VERSION 5.8 ;
BUSBITCHARS "[]" ;
DIVIDERCHAR "/" ;
UNITS
    DATABASE MICRONS 1000 ;
END UNITS

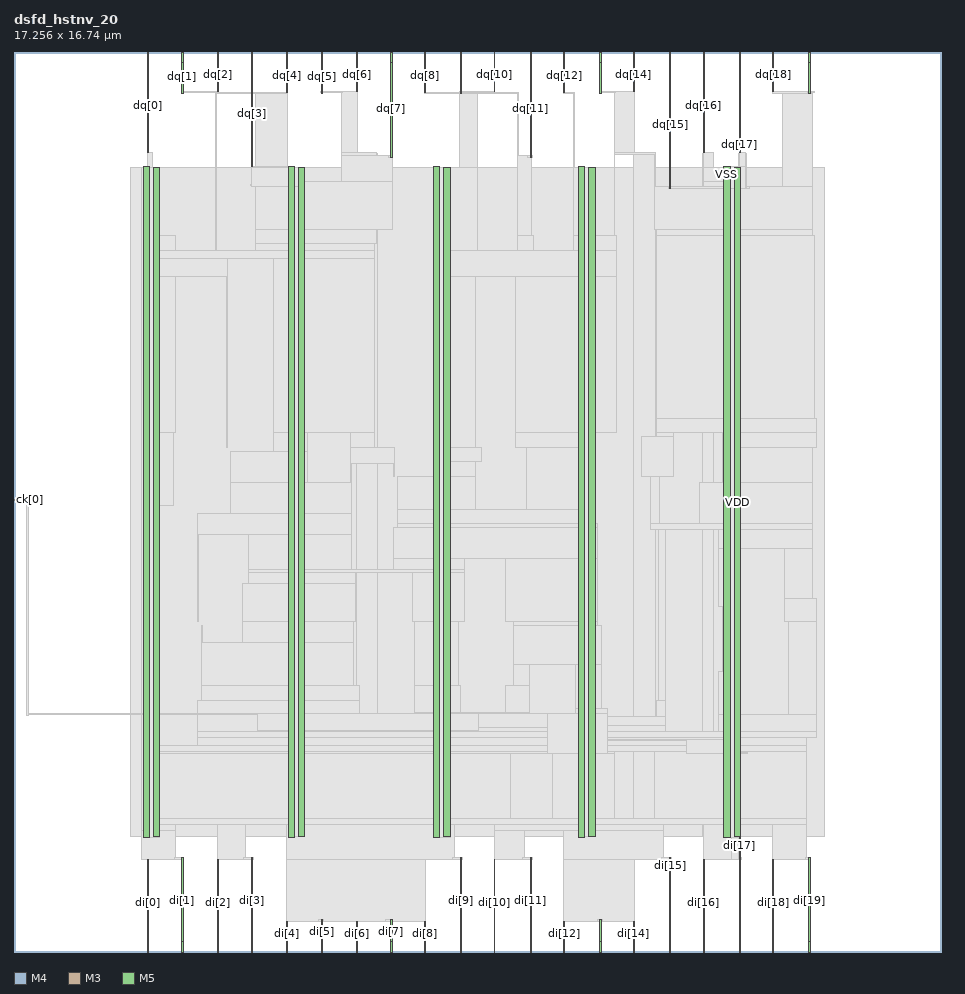
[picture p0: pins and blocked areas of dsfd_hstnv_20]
MACRO dsfd_hstnv_20
  FOREIGN dsfd_hstnv_20 0 0 ;
  CLASS BLOCK ;
  SIZE 17.256 BY 16.74 ;
  PIN ck[0]
    DIRECTION INPUT ;
    USE SIGNAL ;
    PORT
      LAYER M4 ;
        RECT  0 8.4 0.192 8.424 ;
    END
    PORT
      LAYER M4 ;
        RECT  0.156 8.4 0.275 8.424 ;
    END
  END ck[0]
  PIN di[0]
    DIRECTION INPUT ;
    USE SIGNAL ;
    PORT
      LAYER M3 ;
        RECT  2.484 0 2.502 0.144 ;
    END
    PORT
      LAYER M3 ;
        RECT  2.484 0.108 2.502 1.723 ;
    END
  END di[0]
  PIN di[10]
    DIRECTION INPUT ;
    USE SIGNAL ;
    PORT
      LAYER M3 ;
        RECT  8.928 0 8.946 0.144 ;
    END
    PORT
      LAYER M3 ;
        RECT  8.928 0.108 8.946 1.723 ;
    END
  END di[10]
  PIN di[11]
    DIRECTION INPUT ;
    USE SIGNAL ;
    PORT
      LAYER M5 ;
        RECT  9.6 0 9.624 0.192 ;
    END
    PORT
      LAYER M5 ;
        RECT  9.6 0.144 9.624 1.763 ;
    END
  END di[11]
  PIN di[12]
    DIRECTION INPUT ;
    USE SIGNAL ;
    PORT
      LAYER M3 ;
        RECT  10.224 0 10.242 0.144 ;
    END
    PORT
      LAYER M3 ;
        RECT  10.224 0.108 10.242 0.571 ;
    END
  END di[12]
  PIN di[13]
    DIRECTION INPUT ;
    USE SIGNAL ;
    PORT
      LAYER M5 ;
        RECT  10.896 0 10.92 0.192 ;
    END
    PORT
      LAYER M5 ;
        RECT  10.896 0.144 10.92 0.611 ;
    END
  END di[13]
  PIN di[14]
    DIRECTION INPUT ;
    USE SIGNAL ;
    PORT
      LAYER M3 ;
        RECT  11.52 0 11.538 0.144 ;
    END
    PORT
      LAYER M3 ;
        RECT  11.52 0.108 11.538 0.571 ;
    END
  END di[14]
  PIN di[15]
    DIRECTION INPUT ;
    USE SIGNAL ;
    PORT
      LAYER M5 ;
        RECT  12.192 0 12.216 0.192 ;
    END
    PORT
      LAYER M5 ;
        RECT  12.192 0.144 12.216 1.763 ;
    END
  END di[15]
  PIN di[16]
    DIRECTION INPUT ;
    USE SIGNAL ;
    PORT
      LAYER M3 ;
        RECT  12.816 0 12.834 0.144 ;
    END
    PORT
      LAYER M3 ;
        RECT  12.816 0.108 12.834 1.723 ;
    END
  END di[16]
  PIN di[17]
    DIRECTION INPUT ;
    USE SIGNAL ;
    PORT
      LAYER M5 ;
        RECT  13.488 0 13.512 0.192 ;
    END
    PORT
      LAYER M5 ;
        RECT  13.488 0.144 13.512 2.137 ;
    END
  END di[17]
  PIN di[18]
    DIRECTION INPUT ;
    USE SIGNAL ;
    PORT
      LAYER M3 ;
        RECT  14.112 0 14.13 0.144 ;
    END
    PORT
      LAYER M3 ;
        RECT  14.112 0.108 14.13 1.723 ;
    END
  END di[18]
  PIN di[19]
    DIRECTION INPUT ;
    USE SIGNAL ;
    PORT
      LAYER M5 ;
        RECT  14.784 0 14.808 0.192 ;
    END
    PORT
      LAYER M5 ;
        RECT  14.784 0.144 14.808 1.763 ;
    END
  END di[19]
  PIN di[1]
    DIRECTION INPUT ;
    USE SIGNAL ;
    PORT
      LAYER M5 ;
        RECT  3.12 0 3.144 0.192 ;
    END
    PORT
      LAYER M5 ;
        RECT  3.12 0.144 3.144 1.763 ;
    END
  END di[1]
  PIN di[2]
    DIRECTION INPUT ;
    USE SIGNAL ;
    PORT
      LAYER M3 ;
        RECT  3.78 0 3.798 0.144 ;
    END
    PORT
      LAYER M3 ;
        RECT  3.78 0.108 3.798 1.723 ;
    END
  END di[2]
  PIN di[3]
    DIRECTION INPUT ;
    USE SIGNAL ;
    PORT
      LAYER M5 ;
        RECT  4.416 0 4.44 0.192 ;
    END
    PORT
      LAYER M5 ;
        RECT  4.416 0.144 4.44 1.763 ;
    END
  END di[3]
  PIN di[4]
    DIRECTION INPUT ;
    USE SIGNAL ;
    PORT
      LAYER M3 ;
        RECT  5.076 0 5.094 0.144 ;
    END
    PORT
      LAYER M3 ;
        RECT  5.076 0.108 5.094 0.571 ;
    END
  END di[4]
  PIN di[5]
    DIRECTION INPUT ;
    USE SIGNAL ;
    PORT
      LAYER M5 ;
        RECT  5.712 0 5.736 0.192 ;
    END
    PORT
      LAYER M5 ;
        RECT  5.712 0.144 5.736 0.611 ;
    END
  END di[5]
  PIN di[6]
    DIRECTION INPUT ;
    USE SIGNAL ;
    PORT
      LAYER M3 ;
        RECT  6.372 0 6.39 0.144 ;
    END
    PORT
      LAYER M3 ;
        RECT  6.372 0.108 6.39 0.571 ;
    END
  END di[6]
  PIN di[7]
    DIRECTION INPUT ;
    USE SIGNAL ;
    PORT
      LAYER M5 ;
        RECT  7.008 0 7.032 0.192 ;
    END
    PORT
      LAYER M5 ;
        RECT  7.008 0.144 7.032 0.611 ;
    END
  END di[7]
  PIN di[8]
    DIRECTION INPUT ;
    USE SIGNAL ;
    PORT
      LAYER M3 ;
        RECT  7.632 0 7.65 0.144 ;
    END
    PORT
      LAYER M3 ;
        RECT  7.632 0.108 7.65 0.571 ;
    END
  END di[8]
  PIN di[9]
    DIRECTION INPUT ;
    USE SIGNAL ;
    PORT
      LAYER M5 ;
        RECT  8.304 0 8.328 0.192 ;
    END
    PORT
      LAYER M5 ;
        RECT  8.304 0.144 8.328 1.763 ;
    END
  END di[9]
  PIN dq[0]
    DIRECTION OUTPUT ;
    USE SIGNAL ;
    PORT
      LAYER M3 ;
        RECT  2.484 16.596 2.502 16.74 ;
    END
    PORT
      LAYER M3 ;
        RECT  2.484 14.864 2.502 16.62 ;
    END
  END dq[0]
  PIN dq[10]
    DIRECTION OUTPUT ;
    USE SIGNAL ;
    PORT
      LAYER M3 ;
        RECT  8.928 16.596 8.946 16.74 ;
    END
    PORT
      LAYER M3 ;
        RECT  8.928 16.013 8.946 16.62 ;
    END
  END dq[10]
  PIN dq[11]
    DIRECTION OUTPUT ;
    USE SIGNAL ;
    PORT
      LAYER M5 ;
        RECT  9.6 16.548 9.624 16.74 ;
    END
    PORT
      LAYER M5 ;
        RECT  9.6 14.773 9.624 16.592 ;
    END
  END dq[11]
  PIN dq[12]
    DIRECTION OUTPUT ;
    USE SIGNAL ;
    PORT
      LAYER M3 ;
        RECT  10.224 16.596 10.242 16.74 ;
    END
    PORT
      LAYER M3 ;
        RECT  10.224 15.989 10.242 16.62 ;
    END
  END dq[12]
  PIN dq[13]
    DIRECTION OUTPUT ;
    USE SIGNAL ;
    PORT
      LAYER M5 ;
        RECT  10.896 16.548 10.92 16.74 ;
    END
    PORT
      LAYER M5 ;
        RECT  10.896 15.973 10.92 16.592 ;
    END
  END dq[13]
  PIN dq[14]
    DIRECTION OUTPUT ;
    USE SIGNAL ;
    PORT
      LAYER M3 ;
        RECT  11.52 16.596 11.538 16.74 ;
    END
    PORT
      LAYER M3 ;
        RECT  11.52 16.013 11.538 16.62 ;
    END
  END dq[14]
  PIN dq[15]
    DIRECTION OUTPUT ;
    USE SIGNAL ;
    PORT
      LAYER M5 ;
        RECT  12.192 16.548 12.216 16.74 ;
    END
    PORT
      LAYER M5 ;
        RECT  12.192 14.197 12.216 16.592 ;
    END
  END dq[15]
  PIN dq[16]
    DIRECTION OUTPUT ;
    USE SIGNAL ;
    PORT
      LAYER M3 ;
        RECT  12.816 16.596 12.834 16.74 ;
    END
    PORT
      LAYER M3 ;
        RECT  12.816 14.864 12.834 16.62 ;
    END
  END dq[16]
  PIN dq[17]
    DIRECTION OUTPUT ;
    USE SIGNAL ;
    PORT
      LAYER M5 ;
        RECT  13.488 16.548 13.512 16.74 ;
    END
    PORT
      LAYER M5 ;
        RECT  13.488 14.867 13.512 16.592 ;
    END
  END dq[17]
  PIN dq[18]
    DIRECTION OUTPUT ;
    USE SIGNAL ;
    PORT
      LAYER M3 ;
        RECT  14.112 16.596 14.13 16.74 ;
    END
    PORT
      LAYER M3 ;
        RECT  14.112 16.013 14.13 16.62 ;
    END
  END dq[18]
  PIN dq[19]
    DIRECTION OUTPUT ;
    USE SIGNAL ;
    PORT
      LAYER M5 ;
        RECT  14.784 16.548 14.808 16.74 ;
    END
    PORT
      LAYER M5 ;
        RECT  14.784 15.973 14.808 16.592 ;
    END
  END dq[19]
  PIN dq[1]
    DIRECTION OUTPUT ;
    USE SIGNAL ;
    PORT
      LAYER M5 ;
        RECT  3.12 16.548 3.144 16.74 ;
    END
    PORT
      LAYER M5 ;
        RECT  3.12 15.973 3.144 16.592 ;
    END
  END dq[1]
  PIN dq[2]
    DIRECTION OUTPUT ;
    USE SIGNAL ;
    PORT
      LAYER M3 ;
        RECT  3.78 16.596 3.798 16.74 ;
    END
    PORT
      LAYER M3 ;
        RECT  3.78 16.013 3.798 16.62 ;
    END
  END dq[2]
  PIN dq[3]
    DIRECTION OUTPUT ;
    USE SIGNAL ;
    PORT
      LAYER M5 ;
        RECT  4.416 16.548 4.44 16.74 ;
    END
    PORT
      LAYER M5 ;
        RECT  4.416 14.603 4.44 16.592 ;
    END
  END dq[3]
  PIN dq[4]
    DIRECTION OUTPUT ;
    USE SIGNAL ;
    PORT
      LAYER M3 ;
        RECT  5.076 16.596 5.094 16.74 ;
    END
    PORT
      LAYER M3 ;
        RECT  5.076 15.989 5.094 16.62 ;
    END
  END dq[4]
  PIN dq[5]
    DIRECTION OUTPUT ;
    USE SIGNAL ;
    PORT
      LAYER M5 ;
        RECT  5.712 16.548 5.736 16.74 ;
    END
    PORT
      LAYER M5 ;
        RECT  5.712 15.973 5.736 16.592 ;
    END
  END dq[5]
  PIN dq[6]
    DIRECTION OUTPUT ;
    USE SIGNAL ;
    PORT
      LAYER M3 ;
        RECT  6.372 16.596 6.39 16.74 ;
    END
    PORT
      LAYER M3 ;
        RECT  6.372 16.013 6.39 16.62 ;
    END
  END dq[6]
  PIN dq[7]
    DIRECTION OUTPUT ;
    USE SIGNAL ;
    PORT
      LAYER M5 ;
        RECT  7.008 16.548 7.032 16.74 ;
    END
    PORT
      LAYER M5 ;
        RECT  7.008 14.773 7.032 16.592 ;
    END
  END dq[7]
  PIN dq[8]
    DIRECTION OUTPUT ;
    USE SIGNAL ;
    PORT
      LAYER M3 ;
        RECT  7.632 16.596 7.65 16.74 ;
    END
    PORT
      LAYER M3 ;
        RECT  7.632 15.989 7.65 16.62 ;
    END
  END dq[8]
  PIN dq[9]
    DIRECTION OUTPUT ;
    USE SIGNAL ;
    PORT
      LAYER M5 ;
        RECT  8.304 16.548 8.328 16.74 ;
    END
    PORT
      LAYER M5 ;
        RECT  8.304 15.973 8.328 16.592 ;
    END
  END dq[9]
  PIN VDD
    DIRECTION INOUT ;
    USE POWER ;
    PORT
      LAYER M5 ;
        RECT  13.392 2.151 13.512 14.589 ;
        RECT  10.692 2.151 10.812 14.589 ;
        RECT  7.992 2.151 8.112 14.589 ;
        RECT  5.292 2.151 5.412 14.589 ;
        RECT  2.592 2.151 2.712 14.589 ;
    END
  END VDD
  PIN VSS
    DIRECTION INOUT ;
    USE GROUND ;
    PORT
      LAYER M5 ;
        RECT  13.2 2.137 13.32 14.603 ;
        RECT  10.5 2.137 10.62 14.603 ;
        RECT  7.8 2.137 7.92 14.603 ;
        RECT  5.1 2.137 5.22 14.603 ;
        RECT  2.4 2.137 2.52 14.603 ;
    END
  END VSS
  # OT_OBS_CLOSED layer=M5 d_um=1.536 added=0
  OBS
    LAYER RVTN ;
     RECT  2.16 2.16 15.066 2.295 ;
     RECT  2.16 2.565 15.066 2.835 ;
     RECT  2.16 3.105 15.066 3.375 ;
     RECT  2.16 3.645 15.066 3.915 ;
     RECT  2.16 4.185 15.066 4.455 ;
     RECT  2.16 4.725 15.066 4.995 ;
     RECT  2.16 5.265 15.066 5.535 ;
     RECT  2.16 5.805 15.066 6.075 ;
     RECT  2.16 6.345 15.066 6.615 ;
     RECT  2.16 6.885 15.066 7.155 ;
     RECT  2.16 7.425 15.066 7.695 ;
     RECT  2.16 7.965 15.066 8.235 ;
     RECT  2.16 8.505 15.066 8.775 ;
     RECT  2.16 9.045 15.066 9.315 ;
     RECT  2.16 9.585 15.066 9.855 ;
     RECT  2.16 10.125 15.066 10.395 ;
     RECT  2.16 10.665 15.066 10.935 ;
     RECT  2.16 11.205 15.066 11.475 ;
     RECT  2.16 11.745 15.066 12.015 ;
     RECT  2.16 12.285 15.066 12.555 ;
     RECT  2.16 12.825 15.066 13.095 ;
     RECT  2.16 13.365 15.066 13.635 ;
     RECT  2.16 13.905 15.066 14.175 ;
     RECT  2.16 14.445 15.066 14.58 ;
    LAYER RVTP ;
     RECT  2.16 2.295 15.066 2.565 ;
     RECT  2.16 2.835 15.066 3.105 ;
     RECT  2.16 3.375 15.066 3.645 ;
     RECT  2.16 3.915 15.066 4.185 ;
     RECT  2.16 4.455 15.066 4.725 ;
     RECT  2.16 4.995 15.066 5.265 ;
     RECT  2.16 5.535 15.066 5.805 ;
     RECT  2.16 6.075 15.066 6.345 ;
     RECT  2.16 6.615 15.066 6.885 ;
     RECT  2.16 7.155 15.066 7.425 ;
     RECT  2.16 7.695 15.066 7.965 ;
     RECT  2.16 8.235 15.066 8.505 ;
     RECT  2.16 8.775 15.066 9.045 ;
     RECT  2.16 9.315 15.066 9.585 ;
     RECT  2.16 9.855 15.066 10.125 ;
     RECT  2.16 10.395 15.066 10.665 ;
     RECT  2.16 10.935 15.066 11.205 ;
     RECT  2.16 11.475 15.066 11.745 ;
     RECT  2.16 12.015 15.066 12.285 ;
     RECT  2.16 12.555 15.066 12.825 ;
     RECT  2.16 13.095 15.066 13.365 ;
     RECT  2.16 13.635 15.066 13.905 ;
     RECT  2.16 14.175 15.066 14.445 ;
    LAYER M1 ;
     RECT  2.16 2.151 15.066 14.589 ;
    LAYER M2 ;
     RECT  2.16 2.151 2.371 14.589 ;
     RECT  2.371 1.728 2.479 14.589 ;
     RECT  2.479 1.728 2.507 14.859 ;
     RECT  2.507 2.151 2.579 14.859 ;
     RECT  3.775 15.966 4.523 15.984 ;
     RECT  2.579 2.151 6.367 14.589 ;
     RECT  6.367 2.151 6.755 14.859 ;
     RECT  7.627 15.966 9.383 15.984 ;
     RECT  10.219 15.966 10.427 15.984 ;
     RECT  6.755 2.151 11.515 14.589 ;
     RECT  11.515 2.151 11.939 14.859 ;
     RECT  11.939 2.151 12.811 14.589 ;
     RECT  12.811 2.151 13.019 14.859 ;
     RECT  14.107 15.966 14.315 15.984 ;
     RECT  13.019 2.151 15.066 14.589 ;
    LAYER M3 ;
     RECT  5.076 0.571 7.65 1.723 ;
     RECT  10.224 0.571 11.538 1.723 ;
     RECT  2.376 1.723 3.006 2.255 ;
     RECT  8.928 1.723 9.486 2.263 ;
     RECT  10.224 1.723 12.078 2.263 ;
     RECT  2.415 2.255 3.006 2.371 ;
     RECT  3.78 1.723 4.302 2.371 ;
     RECT  5.076 1.723 8.19 2.371 ;
     RECT  8.928 2.263 12.078 2.371 ;
     RECT  12.816 1.723 13.374 2.371 ;
     RECT  14.112 1.723 14.742 2.371 ;
     RECT  2.415 2.371 14.742 2.489 ;
     RECT  2.415 2.489 9.234 3.691 ;
     RECT  10.008 2.489 11.178 3.691 ;
     RECT  2.415 3.691 11.178 3.721 ;
     RECT  11.916 2.489 14.742 3.721 ;
     RECT  2.415 3.721 14.742 3.839 ;
     RECT  3.42 3.839 14.742 3.991 ;
     RECT  3.42 3.991 14.922 4.109 ;
     RECT  7.452 4.109 12.114 4.205 ;
     RECT  10.44 4.205 12.114 4.379 ;
     RECT  13.104 4.109 14.922 4.415 ;
     RECT  7.452 4.205 9.594 4.451 ;
     RECT  10.44 4.379 11.034 4.523 ;
     RECT  3.42 4.109 6.426 4.685 ;
     RECT  11.952 4.379 12.114 4.685 ;
     RECT  3.492 4.685 6.426 4.955 ;
     RECT  7.452 4.451 8.298 4.955 ;
     RECT  9.144 4.451 9.594 4.955 ;
     RECT  13.104 4.415 13.497 5.225 ;
     RECT  9.288 4.955 9.594 5.341 ;
     RECT  10.44 4.523 10.926 5.341 ;
     RECT  3.492 4.955 6.318 5.765 ;
     RECT  3.492 5.765 3.51 6.071 ;
     RECT  9.288 5.341 10.926 6.071 ;
     RECT  4.248 5.765 6.318 6.151 ;
     RECT  7.452 4.955 8.262 6.151 ;
     RECT  9.288 6.071 10.854 6.151 ;
     RECT  14.4 4.415 14.922 6.151 ;
     RECT  13.176 5.225 13.497 6.421 ;
     RECT  14.328 6.151 14.922 6.575 ;
     RECT  4.248 6.151 6.354 6.845 ;
     RECT  4.356 6.845 6.354 7.051 ;
     RECT  7.416 6.151 8.37 7.051 ;
     RECT  4.356 7.051 8.37 7.115 ;
     RECT  7.056 7.115 8.37 7.321 ;
     RECT  9.144 6.151 10.854 7.321 ;
     RECT  13.104 6.421 13.497 7.501 ;
     RECT  14.328 6.575 14.85 7.501 ;
     RECT  3.42 6.151 3.438 7.771 ;
     RECT  4.356 7.115 6.282 7.771 ;
     RECT  11.988 4.685 12.114 7.861 ;
     RECT  13.104 7.501 14.85 7.861 ;
     RECT  7.056 7.321 10.854 7.889 ;
     RECT  7.128 7.889 10.854 7.961 ;
     RECT  11.844 7.861 14.85 7.961 ;
     RECT  3.42 7.771 6.282 8.159 ;
     RECT  7.128 7.961 10.797 8.231 ;
     RECT  2.415 3.839 2.697 8.311 ;
     RECT  4.032 8.159 6.282 8.735 ;
     RECT  12.744 7.961 14.85 8.735 ;
     RECT  7.128 8.231 8.586 8.843 ;
     RECT  11.844 7.961 12.006 8.851 ;
     RECT  6.264 8.735 6.282 9.085 ;
     RECT  7.056 8.851 7.074 9.085 ;
     RECT  7.815 8.843 8.586 9.121 ;
     RECT  4.032 8.735 5.454 9.311 ;
     RECT  6.264 9.085 7.074 9.383 ;
     RECT  7.815 9.121 8.694 9.383 ;
     RECT  9.54 8.231 10.797 9.391 ;
     RECT  13.176 8.735 14.85 9.391 ;
     RECT  11.664 8.851 12.258 9.581 ;
     RECT  2.415 8.311 2.97 9.661 ;
     RECT  4.824 9.311 5.454 9.661 ;
     RECT  6.264 9.383 6.714 9.661 ;
     RECT  9.324 9.391 10.797 9.661 ;
     RECT  11.952 9.581 12.258 9.661 ;
     RECT  13.176 9.391 14.922 9.661 ;
     RECT  11.952 9.661 14.922 9.923 ;
     RECT  2.415 9.661 3.006 12.559 ;
     RECT  3.96 9.391 3.978 12.559 ;
     RECT  7.815 9.383 8.586 12.559 ;
     RECT  9.324 9.661 11.214 12.559 ;
     RECT  2.415 12.559 3.978 12.901 ;
     RECT  4.824 9.661 6.714 12.901 ;
     RECT  2.415 12.901 6.714 13.055 ;
     RECT  7.815 12.559 11.214 13.055 ;
     RECT  4.5 13.055 6.714 13.171 ;
     RECT  2.415 13.055 3.006 13.325 ;
     RECT  9.36 13.055 9.666 13.325 ;
     RECT  10.404 13.055 11.214 13.325 ;
     RECT  11.952 9.923 14.886 13.325 ;
     RECT  4.5 13.171 6.75 13.441 ;
     RECT  11.952 13.325 14.85 13.441 ;
     RECT  11.916 13.441 14.85 14.237 ;
     RECT  2.415 13.325 2.697 14.327 ;
     RECT  4.5 13.441 7.038 14.327 ;
     RECT  12.816 14.237 13.497 14.327 ;
     RECT  2.415 14.327 2.574 14.597 ;
     RECT  4.5 14.327 5.205 14.597 ;
     RECT  7.815 13.055 8.622 14.597 ;
     RECT  10.404 13.325 11.178 14.597 ;
     RECT  12.816 14.327 13.305 14.597 ;
     RECT  6.084 14.327 7.038 14.813 ;
     RECT  9.36 13.325 9.63 14.813 ;
     RECT  11.16 14.597 11.178 14.836 ;
     RECT  11.916 14.237 11.934 14.836 ;
     RECT  2.484 14.597 2.574 14.864 ;
     RECT  6.084 14.813 6.75 14.864 ;
     RECT  11.16 14.836 11.934 14.864 ;
     RECT  12.816 14.597 13.014 14.864 ;
     RECT  3.744 13.055 3.762 15.961 ;
     RECT  4.5 14.597 5.094 15.961 ;
     RECT  8.28 14.597 8.622 15.961 ;
     RECT  9.36 14.813 9.378 15.961 ;
     RECT  10.404 14.597 10.422 15.961 ;
     RECT  14.292 14.237 14.85 15.961 ;
     RECT  3.744 15.961 5.094 15.989 ;
     RECT  7.632 15.961 9.378 15.989 ;
     RECT  10.224 15.961 10.422 15.989 ;
     RECT  3.744 15.989 3.798 16.013 ;
     RECT  6.084 14.864 6.39 16.013 ;
     RECT  8.604 15.989 8.946 16.013 ;
     RECT  11.16 14.864 11.538 16.013 ;
     RECT  14.112 15.961 14.85 16.013 ;
    LAYER M4 ;
     RECT  0.229 4.416 2.408 4.44 ;
     RECT  2.408 2.148 2.512 14.592 ;
     RECT  2.512 2.148 2.704 14.322 ;
     RECT  2.977 1.728 3.155 1.752 ;
     RECT  3.109 15.984 3.773 16.008 ;
     RECT  4.273 1.728 4.451 1.752 ;
     RECT  2.704 4.416 4.525 4.44 ;
     RECT  4.525 4.128 5.108 4.44 ;
     RECT  4.405 14.256 5.108 14.28 ;
     RECT  5.108 2.148 5.212 14.592 ;
     RECT  5.212 2.418 5.404 14.322 ;
     RECT  5.669 0.576 5.753 0.6 ;
     RECT  5.701 15.984 6.113 16.008 ;
     RECT  6.901 0.576 7.043 0.6 ;
     RECT  6.965 14.784 7.049 14.808 ;
     RECT  5.404 4.128 7.808 4.44 ;
     RECT  7.808 2.148 7.912 14.592 ;
     RECT  7.912 2.148 8.104 14.322 ;
     RECT  8.161 1.728 8.339 1.752 ;
     RECT  8.104 4.128 8.633 4.44 ;
     RECT  8.293 15.984 8.633 16.008 ;
     RECT  9.457 1.728 9.635 1.752 ;
     RECT  9.557 14.784 9.641 14.808 ;
     RECT  8.633 4.176 9.925 4.44 ;
     RECT  9.925 3.696 10.508 4.44 ;
     RECT  10.508 2.148 10.612 14.592 ;
     RECT  10.612 2.418 10.804 14.322 ;
     RECT  10.861 0.576 10.945 0.6 ;
     RECT  10.804 3.696 11.045 4.44 ;
     RECT  10.885 15.984 11.189 16.008 ;
     RECT  12.049 1.728 12.227 1.752 ;
     RECT  11.045 3.936 12.517 3.96 ;
     RECT  12.517 3.696 13.208 3.96 ;
     RECT  12.181 14.208 13.208 14.232 ;
     RECT  13.208 2.148 13.345 14.592 ;
     RECT  13.345 1.728 13.477 14.592 ;
     RECT  13.477 1.728 13.504 14.856 ;
     RECT  13.504 1.728 13.523 1.752 ;
     RECT  13.504 14.208 13.619 14.856 ;
     RECT  13.504 3.696 13.637 3.72 ;
     RECT  13.619 14.208 13.673 14.232 ;
     RECT  14.713 1.728 14.819 1.752 ;
     RECT  14.757 15.984 14.88 16.008 ;
    LAYER M5 ;
     RECT  5.1 2.137 5.22 2.151 ;
     RECT  10.5 2.137 10.62 2.151 ;
     RECT  0.24 4.405 0.264 8.435 ;
     RECT  13.2 2.137 13.512 14.197 ;
     RECT  5.1 2.151 5.412 14.245 ;
     RECT  2.4 2.137 2.712 14.589 ;
     RECT  4.416 14.245 5.412 14.589 ;
     RECT  7.8 2.137 8.112 14.589 ;
     RECT  10.5 2.151 10.812 14.589 ;
     RECT  2.4 14.589 2.52 14.603 ;
     RECT  4.416 14.589 5.22 14.603 ;
     RECT  7.8 14.589 7.92 14.603 ;
     RECT  10.5 14.589 10.62 14.603 ;
     RECT  13.2 14.197 13.608 14.603 ;
     RECT  13.488 14.603 13.608 14.867 ;
  END
END dsfd_hstnv_20
END LIBRARY
